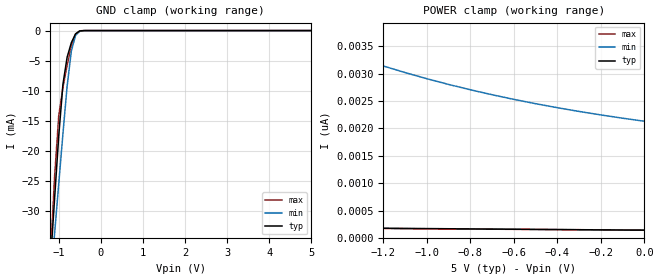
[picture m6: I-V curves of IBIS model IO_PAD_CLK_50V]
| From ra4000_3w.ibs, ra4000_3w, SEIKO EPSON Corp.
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[Model]   IO_PAD_CLK_50V
Model_type Input
Polarity Non-Inverting
Vinh=3.50
Vinl=1.50
C_comp   2.5p   2.0p   3.0p
[Temperature Range] 25   125   -40
[Voltage Range]   5.00   4.50   5.50
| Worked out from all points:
|   GND clamp passes 1 mA (typ) near -0.63 V on its own axis
[GND Clamp]
-5V       -463.1mA   -375.9mA   -569.5mA
-1.2V     -38.93mA   -42.42mA   -37.92mA
-1.1V     -28.22mA   -34mA      -24.54mA
-1V       -17.62mA   -25.59mA   -14.21mA
-900mV    -8.989mA   -17.22mA   -9.509mA
-800mV    -4.45mA    -9.278mA   -5.815mA
-700mV    -2.032mA   -3.427mA   -2.638mA
-600mV    -545.3uA   -804.8uA   -605.9uA
-500mV    -56.89uA   -135.5uA   -35.53uA
-300mV    -121.9nA   -1.689uA   -9.346nA
5V        146.4pA    2.451nA    134.8pA
[POWER Clamp]
-5V       391.6pA    18.99nA    8.229uA
-4.7V     365.3pA    16.56nA    4.189nA
-4.6V     357.2pA    15.81nA    298.1pA
-4.5V     349.3pA    15.09nA    253.6pA
-1.7V     199.2pA    3.874nA    187.2pA
-1.6V     195.6pA    3.707nA    184.9pA
-1.4V     188.6pA    3.403nA    180.3pA
-1.2V     181.9pA    3.138nA    175.7pA
-1V       175.5pA    2.906nA    171.1pA
-800mV    169.3pA    2.705nA    166.4pA
-400mV    157.5pA    2.378nA    157.2pA
0V        146.4pA    2.131nA    148pA
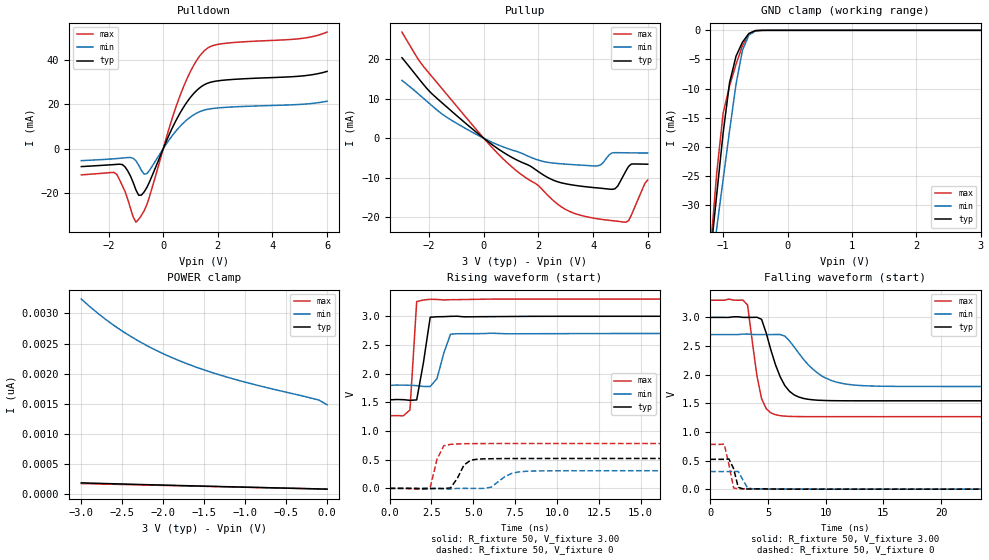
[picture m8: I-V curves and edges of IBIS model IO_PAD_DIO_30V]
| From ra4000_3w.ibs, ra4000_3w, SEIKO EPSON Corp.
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[Model]   IO_PAD_DIO_30V
Model_type I/O
Enable Active-High
Polarity Non-Inverting
Vinh=2.10
Vinl=0.90
Vmeas=1.50
C_comp   2.5p   2.0p   3.0p
[Temperature Range] 25   125   -40
[Voltage Range]   3.00   2.70   3.30
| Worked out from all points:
|   slope of the pulldown table from 0 to 0.45 V, typ, clamps not added: 36.6 ohm
|   slope of the pullup table from 0 to 0.45 V, typ, clamps not added: 193 ohm
|   GND clamp passes 1 mA (typ) near -0.63 V on its own axis
|   falling waveform, R_fixture 50, V_fixture 3.00: 20-80 % time 1.52ns typ, 2.54ns min, 915ps max; typ from 3 V to 1.54 V
|   falling waveform, R_fixture 50, V_fixture 0: 20-80 % time 453ps typ, 520ps min, 492ps max; typ from 0.521 V to 0 V
|   rising waveform, R_fixture 50, V_fixture 3.00: 20-80 % time 486ps typ, 547ps min, 261ps max; typ from 1.54 V to 3 V
|   rising waveform, R_fixture 50, V_fixture 0: 20-80 % time 613ps typ, 946ps min, 494ps max; typ from 0 V to 0.521 V
[Pullup]
-3V       20.45mA    14.69mA    26.95mA
-2.4V     15.29mA    11.28mA    20.02mA
-1.9V     11.29mA    8.266mA    15.65mA
300mV     -1.589mA   -1mA       -2.327mA
1.2V      -5.477mA   -3.33mA    -8.267mA
2V        -8.47mA    -5.542mA   -12.03mA
2.9V      -11.4mA    -6.501mA   -17.67mA
4.2V      -12.61mA   -6.947mA   -20.45mA
4.8V      -12.81mA   -3.639mA   -20.96mA
5.2V      -8.293mA   -3.674mA   -21.28mA
5.4V      -6.536mA   -3.691mA   -19.5mA
6V        -6.57mA    -3.743mA   -10.6mA
[Pulldown]
-3V       -8.089mA   -5.399mA   -11.82mA
-1.7V     -7.088mA   -4.452mA   -11.64mA
-1.4V     -8.196mA   -4.116mA   -19.3mA
-1V       -18.62mA   -5.471mA   -33.2mA
-800mV    -20.97mA   -9.81mA    -30.13mA
-600mV    -17.54mA   -11.26mA   -25.25mA
600mV     15.77mA    9.868mA    23.45mA
1.1V      24.7mA     15.17mA    37.31mA
1.5V      28.87mA    17.43mA    44.2mA
2.1V      30.79mA    18.51mA    47.31mA
5V        32.75mA    19.99mA    49.7mA
6V        34.91mA    21.45mA    52.66mA
[GND Clamp]
-3V       -252mA     -212.3mA   -302.4mA
-1.2V     -38.9mA    -42.39mA   -37.89mA
-1.1V     -28.19mA   -33.97mA   -24.51mA
-1V       -17.59mA   -25.56mA   -14.19mA
-900mV    -8.971mA   -17.19mA   -9.505mA
-800mV    -4.445mA   -9.255mA   -5.814mA
-700mV    -2.032mA   -3.414mA   -2.637mA
-600mV    -545.2uA   -802.7uA   -605.7uA
-500mV    -56.87uA   -135.4uA   -35.51uA
-400mV    -3.146uA   -16.86uA   -733.4nA
3V        88.06pA    1.633nA    79.41pA
[POWER Clamp]
-3V       192.6pA    3.238nA    181.4pA
-2.8V     184.8pA    3.004nA    175.2pA
-2.7V     181pA      2.898nA    172.1pA
-2.5V     173.5pA    2.708nA    165.9pA
-2.4V     169.8pA    2.622nA    162.8pA
-2.2V     162.6pA    2.467nA    156.6pA
-1.9V     152pA      2.272nA    147.3pA
-1.6V     141.6pA    2.111nA    138pA
-1.3V     131.5pA    1.977nA    128.8pA
-900mV    118.2pA    1.826nA    116.5pA
-100mV    91.86pA    1.565nA    92.28pA
0V        88.06pA    1.486nA    89.13pA
[Falling Waveform]
R_fixture=50
V_fixture=3.00
V_fixture_min=2.70
V_fixture_max=3.30
0s        3V         2.7V       3.3V
3.232ns   3V         2.71V      3.217V
4.04ns    3.003V     2.7V       1.985V
4.444ns   2.967V     2.7V       1.583V
5.657ns   2.17V      2.702V     1.3V
6.465ns   1.808V     2.673V     1.276V
7.273ns   1.646V     2.484V     1.269V
9.293ns   1.554V     2.03V      1.266V
11.72ns   1.544V     1.836V     1.266V
40ns      1.543V     1.794V     1.266V
[Falling Waveform]
R_fixture=50
V_fixture=0
V_fixture_min=0
V_fixture_max=0
0s        521.3mV    307.8mV    782mV
1.212ns   520.7mV    307.2mV    786.6mV
1.616ns   527.1mV    307mV      429.8mV
2.02ns    360.1mV    312.2mV    20.35mV
2.424ns   32.68mV    308.5mV    5.629mV
2.828ns   6.643mV    160.5mV    6.295mV
3.232ns   3.001mV    20.56mV    10.48mV
3.636ns   2.449mV    7.464mV    4.281mV
4.04ns    4.909mV    3.312mV    2.495mV
40ns      4.189uV    7.097uV    4.522uV
[Rising Waveform]
R_fixture=50
V_fixture=3.00
V_fixture_min=2.70
V_fixture_max=3.30
0s        1.543V     1.794V     1.266V
808.1ps   1.546V     1.799V     1.264V
1.212ns   1.535V     1.798V     1.366V
1.616ns   1.542V     1.791V     3.256V
2.02ns    2.193V     1.776V     3.284V
2.424ns   2.983V     1.776V     3.296V
2.828ns   2.992V     1.913V     3.293V
3.232ns   2.993V     2.353V     3.284V
3.636ns   2.999V     2.688V     3.289V
40ns      3V         2.7V       3.3V
[Rising Waveform]
R_fixture=50
V_fixture=0
V_fixture_min=0
V_fixture_max=0
0s        495.5pV    2.33nV     407.6pV
2.424ns   -5.108mV   -322.5uV   15.85mV
2.828ns   -136.3uV   -3.075mV   504.1mV
3.232ns   -1.277mV   -8.403mV   742.2mV
3.636ns   7.819mV    -11.04mV   767.4mV
4.444ns   408.1mV    -66.09uV   778mV
5.253ns   509.4mV    -1.226mV   780.7mV
7.273ns   520mV      258mV      781.6mV
8.485ns   520.8mV    301.5mV    781.8mV
40ns      521.3mV    307.8mV    782mV
[Ramp]
R_load=50
dV/dt_r   3.128E-1/5.233E-10   1.847E-1/9.046E-10   4.692E-1/3.239E-10
dV/dt_f   8.743E-1/1.509E-9   5.439E-1/2.535E-9   1.220E+0/8.767E-10
|[End   IO_PAD_DIO_30V
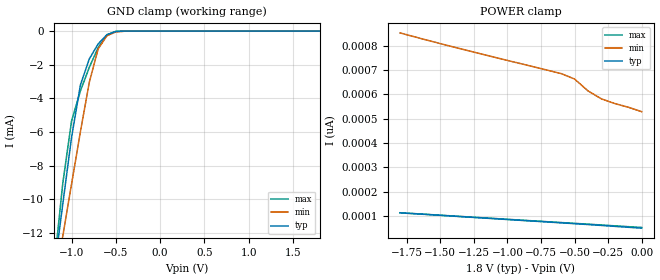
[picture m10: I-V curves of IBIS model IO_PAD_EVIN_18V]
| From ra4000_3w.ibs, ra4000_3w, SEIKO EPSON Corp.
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[Model]   IO_PAD_EVIN_18V
Model_type Input
Polarity Non-Inverting
Vinh=1.26
Vinl=0.54
C_comp   2.5p   2.0p   3.0p
[Temperature Range] 25   125   -40
[Voltage Range]   1.80   1.60   2.00
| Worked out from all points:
|   GND clamp passes 1 mA (typ) near -0.73 V on its own axis
[GND Clamp]
-1.8V     -39.05mA   -34.4mA    -45.23mA
-1.2V     -14.37mA   -15.35mA   -14.17mA
-1.1V     -10.32mA   -12.21mA   -9.088mA
-1V       -6.317mA   -9.085mA   -5.34mA
-900mV    -3.202mA   -5.982mA   -3.555mA
-800mV    -1.659mA   -3.049mA   -2.159mA
-700mV    -764.8uA   -1.065mA   -984.1uA
-600mV    -208.2uA   -273.4uA   -229.3uA
-500mV    -22.05uA   -51.05uA   -13.65uA
-400mV    -1.254uA   -6.762uA   -297.2nA
1.8V      49.12pA    562.5pA    45.5pA
[POWER Clamp]
-1.8V     112.3pA    853.6pA    112.7pA
-1.3V     95.01pA    781.3pA    95.78pA
-600mV    71.04pA    685.9pA    72.27pA
-500mV    67.63pA    663.5pA    68.95pA
-400mV    64.08pA    614.7pA    65.65pA
-300mV    60.31pA    581.7pA    62.14pA
-200mV    56.52pA    562.5pA    58.62pA
-100mV    52.78pA    547.4pA    55.27pA
0V        49.12pA    528.9pA    52.01pA
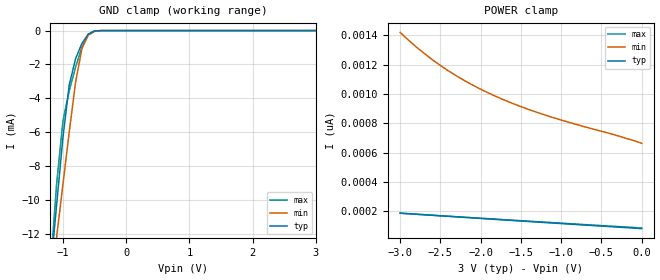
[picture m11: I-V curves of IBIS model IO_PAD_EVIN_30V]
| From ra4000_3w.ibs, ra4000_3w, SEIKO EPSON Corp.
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[Model]   IO_PAD_EVIN_30V
Model_type Input
Polarity Non-Inverting
Vinh=2.10
Vinl=0.90
C_comp   2.5p   2.0p   3.0p
[Temperature Range] 25   125   -40
[Voltage Range]   3.00   2.70   3.30
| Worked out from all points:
|   GND clamp passes 1 mA (typ) near -0.73 V on its own axis
[GND Clamp]
-3V       -89.31mA   -73.46mA   -108.5mA
-1.2V     -14.37mA   -15.35mA   -14.18mA
-1.1V     -10.32mA   -12.21mA   -9.09mA
-1V       -6.32mA    -9.088mA   -5.342mA
-900mV    -3.206mA   -5.985mA   -3.556mA
-800mV    -1.66mA    -3.053mA   -2.159mA
-700mV    -764.8uA   -1.068mA   -984.1uA
-600mV    -208.2uA   -273.9uA   -229.3uA
-500mV    -22.05uA   -51.06uA   -13.65uA
-400mV    -1.255uA   -6.762uA   -297.2nA
3V        81.03pA    716pA      75.98pA
[POWER Clamp]
-3V       187.2pA    1.421nA    186.2pA
-2.8V     179.8pA    1.322nA    179.4pA
-2.7V     176.1pA    1.277nA    176pA
-2.5V     168.8pA    1.195nA    169.3pA
-2.4V     165.2pA    1.159nA    165.9pA
-2.2V     157.9pA    1.092nA    159.1pA
-1.9V     147.2pA    1.006nA    148.9pA
-1.6V     136.7pA    935.4pA    138.8pA
-1.2V     122.7pA    856.9pA    125.3pA
-800mV    108.8pA    790.7pA    111.8pA
-300mV    91.79pA    716pA      95.32pA
0V        81.03pA    663.7pA    85.81pA
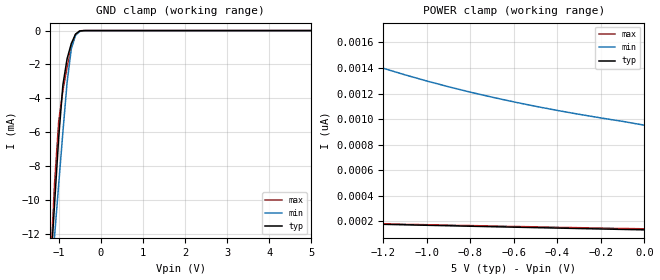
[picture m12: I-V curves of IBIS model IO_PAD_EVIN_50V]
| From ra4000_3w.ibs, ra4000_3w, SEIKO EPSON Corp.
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[Model]   IO_PAD_EVIN_50V
Model_type Input
Polarity Non-Inverting
Vinh=3.50
Vinl=1.50
C_comp   2.5p   2.0p   3.0p
[Temperature Range] 25   125   -40
[Voltage Range]   5.00   4.50   5.50
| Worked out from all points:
|   GND clamp passes 1 mA (typ) near -0.73 V on its own axis
[GND Clamp]
-5V       -175.4mA   -140.5mA   -216.8mA
-1.2V     -14.37mA   -15.35mA   -14.18mA
-1.1V     -10.32mA   -12.22mA   -9.091mA
-1V       -6.322mA   -9.09mA    -5.343mA
-900mV    -3.208mA   -5.988mA   -3.556mA
-800mV    -1.661mA   -3.056mA   -2.159mA
-700mV    -764.8uA   -1.07mA    -984.1uA
-600mV    -208.2uA   -274.3uA   -229.3uA
-500mV    -22.05uA   -51.06uA   -13.65uA
-300mV    -50.67nA   -698.3nA   -4.135nA
5V        134.5pA    1.1nA      126pA
[POWER Clamp]
-5V       359.1pA    7.929nA    8.229uA
-4.7V     340.1pA    6.937nA    4.232nA
-4.6V     334.1pA    6.63nA     340.4pA
-4.5V     328.3pA    6.335nA    294.8pA
-3.2V     261pA      3.428nA    249.1pA
-1.7V     197pA      1.71nA     198.1pA
-1.6V     193pA      1.639nA    194.8pA
-1.4V     185.3pA    1.511nA    188pA
-1.2V     177.7pA    1.397nA    181.2pA
-900mV    166.5pA    1.253nA    171.1pA
-500mV    151.9pA    1.1nA      157.8pA
0V        134.5pA    952.8pA    142.5pA
